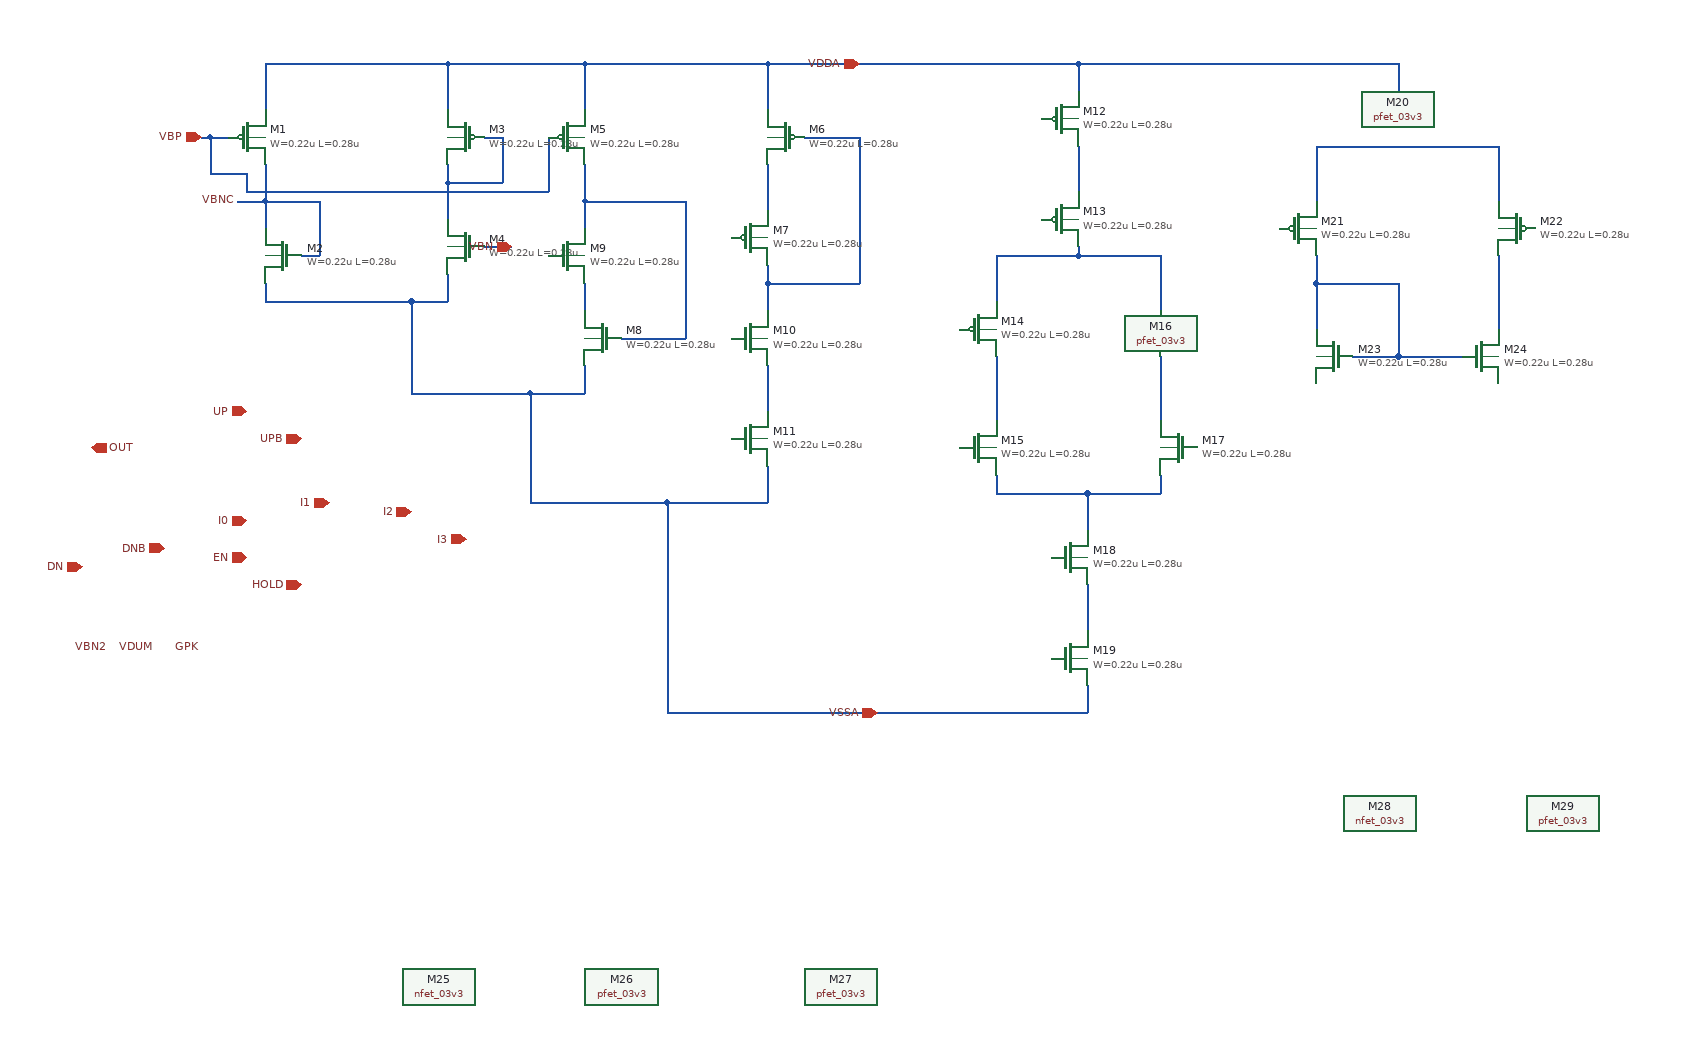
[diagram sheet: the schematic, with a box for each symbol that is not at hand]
v {xschem version=3.4.8RC file_version=1.3}
G {}
K {}
V {}
S {}
F {}
E {}
N -330 -30 -330 -0 {lab=VBNC}
N -130 -50 -130 -10 {lab=#net1}
N -290 30 -270 30 {lab=VBNC}
N -270 -30 -270 30 {lab=VBNC}
N -330 -30 -270 -30 {lab=VBNC}
N -330 -70 -330 -30 {lab=VBNC}
N -90 -100 -70 -100 {lab=#net1}
N -70 -100 -70 -50 {lab=#net1}
N -130 -50 -70 -50 {lab=#net1}
N -130 -70 -130 -50 {lab=#net1}
N -330 -180 -330 -130 {lab=VDDA}
N -330 -180 -130 -180 {lab=VDDA}
N -130 -180 -130 -130 {lab=VDDA}
N 20 -30 130 -30 {lab=#net2}
N 20 -70 20 -30 {lab=#net2}
N 260 -100 320 -100 {lab=#net3}
N 20 -180 20 -130 {lab=VDDA}
N 20 -180 220 -180 {lab=VDDA}
N 220 -180 220 -130 {lab=VDDA}
N -130 -180 20 -180 {lab=VDDA}
N 220 -70 220 -20 {lab=#net4}
N 220 150 220 200 {lab=#net5}
N 220 60 220 90 {lab=#net3}
N 320 -100 320 60 {lab=#net3}
N 220 60 320 60 {lab=#net3}
N 220 40 220 60 {lab=#net3}
N 20 60 20 90 {lab=#net6}
N 20 -30 20 -0 {lab=#net2}
N 60 120 130 120 {lab=#net2}
N 130 -30 130 120 {lab=#net2}
N 570 390 570 440 {lab=#net7}
N 560 -90 560 -40 {lab=#net8}
N 470 30 470 80 {lab=#net9}
N 560 30 650 30 {lab=#net9}
N 650 30 650 90 {lab=#net9}
N 560 20 560 30 {lab=#net9}
N 470 30 560 30 {lab=#net9}
N 470 140 470 210 {lab=#net10}
N 650 140 650 210 {lab=#net11}
N 470 270 470 290 {lab=#net12}
N 570 290 650 290 {lab=#net12}
N 650 270 650 290 {lab=#net12}
N 570 290 570 330 {lab=#net12}
N 470 290 570 290 {lab=#net12}
N 820 -90 820 -30 {lab=#net13}
N 820 -90 1020 -90 {lab=#net13}
N 1020 -90 1020 -30 {lab=#net13}
N 820 60 820 110 {lab=#net14}
N 1020 30 1020 110 {lab=#net15}
N 910 140 980 140 {lab=#net14}
N 820 60 910 60 {lab=#net14}
N 820 30 820 60 {lab=#net14}
N 910 60 910 140 {lab=#net14}
N 860 140 910 140 {lab=#net14}
N 560 -180 910 -180 {lab=VDDA}
N 910 -180 910 -150 {lab=VDDA}
N 560 -180 560 -150 {lab=VDDA}
N 220 -180 560 -180 {lab=VDDA}
N -390 -100 -370 -100 {lab=VBP}
N -360 -30 -330 -30 {lab=VBNC}
N -330 60 -330 80 {lab=VSSA}
N -170 80 -130 80 {lab=VSSA}
N -130 50 -130 80 {lab=VSSA}
N 20 150 20 180 {lab=VSSA}
N -40 180 20 180 {lab=VSSA}
N -170 80 -170 180 {lab=VSSA}
N -330 80 -170 80 {lab=VSSA}
N 220 260 220 300 {lab=VSSA}
N 110 300 220 300 {lab=VSSA}
N -40 180 -40 300 {lab=VSSA}
N -170 180 -40 180 {lab=VSSA}
N 570 500 570 530 {lab=VSSA}
N 110 530 570 530 {lab=VSSA}
N 110 300 110 530 {lab=VSSA}
N -40 300 110 300 {lab=VSSA}
N -20 -100 -20 -40 {lab=VBP}
N -350 -40 -20 -40 {lab=VBP}
N -350 -60 -350 -40 {lab=VBP}
N -390 -60 -350 -60 {lab=VBP}
N -390 -100 -390 -60 {lab=VBP}
N -400 -100 -390 -100 {lab=VBP}
N -90 20 -60 20 {lab=VBN}
C {/foss/pdks/gf180mcuD/libs.tech/xschem/symbols/pfet_03v3.sym} -350 -100 0 0 {name=M1
L=0.28u
W=0.22u
nf=1
m=1
ad="'int((nf+1)/2) * W/nf * 0.18u'"
pd="'2*int((nf+1)/2) * (W/nf + 0.18u)'"
as="'int((nf+2)/2) * W/nf * 0.18u'"
ps="'2*int((nf+2)/2) * (W/nf + 0.18u)'"
nrd="'0.18u / W'" nrs="'0.18u / W'"
sa=0 sb=0 sd=0
model=pfet_03v3
spiceprefix=X
}
C {/foss/pdks/gf180mcuD/libs.tech/xschem/symbols/nfet_03v3.sym} -310 30 2 0 {name=M2
L=0.28u
W=0.22u
nf=1
m=1
ad="'int((nf+1)/2) * W/nf * 0.18u'"
pd="'2*int((nf+1)/2) * (W/nf + 0.18u)'"
as="'int((nf+2)/2) * W/nf * 0.18u'"
ps="'2*int((nf+2)/2) * (W/nf + 0.18u)'"
nrd="'0.18u / W'" nrs="'0.18u / W'"
sa=0 sb=0 sd=0
model=nfet_03v3
spiceprefix=X
}
C {/foss/pdks/gf180mcuD/libs.tech/xschem/symbols/pfet_03v3.sym} -110 -100 0 1 {name=M3
L=0.28u
W=0.22u
nf=1
m=1
ad="'int((nf+1)/2) * W/nf * 0.18u'"
pd="'2*int((nf+1)/2) * (W/nf + 0.18u)'"
as="'int((nf+2)/2) * W/nf * 0.18u'"
ps="'2*int((nf+2)/2) * (W/nf + 0.18u)'"
nrd="'0.18u / W'" nrs="'0.18u / W'"
sa=0 sb=0 sd=0
model=pfet_03v3
spiceprefix=X
}
C {/foss/pdks/gf180mcuD/libs.tech/xschem/symbols/nfet_03v3.sym} -110 20 2 0 {name=M4
L=0.28u
W=0.22u
nf=1
m=1
ad="'int((nf+1)/2) * W/nf * 0.18u'"
pd="'2*int((nf+1)/2) * (W/nf + 0.18u)'"
as="'int((nf+2)/2) * W/nf * 0.18u'"
ps="'2*int((nf+2)/2) * (W/nf + 0.18u)'"
nrd="'0.18u / W'" nrs="'0.18u / W'"
sa=0 sb=0 sd=0
model=nfet_03v3
spiceprefix=X
}
C {/foss/pdks/gf180mcuD/libs.tech/xschem/symbols/pfet_03v3.sym} 0 -100 0 0 {name=M5
L=0.28u
W=0.22u
nf=1
m=1
ad="'int((nf+1)/2) * W/nf * 0.18u'"
pd="'2*int((nf+1)/2) * (W/nf + 0.18u)'"
as="'int((nf+2)/2) * W/nf * 0.18u'"
ps="'2*int((nf+2)/2) * (W/nf + 0.18u)'"
nrd="'0.18u / W'" nrs="'0.18u / W'"
sa=0 sb=0 sd=0
model=pfet_03v3
spiceprefix=X
}
C {/foss/pdks/gf180mcuD/libs.tech/xschem/symbols/pfet_03v3.sym} 240 -100 0 1 {name=M6
L=0.28u
W=0.22u
nf=1
m=1
ad="'int((nf+1)/2) * W/nf * 0.18u'"
pd="'2*int((nf+1)/2) * (W/nf + 0.18u)'"
as="'int((nf+2)/2) * W/nf * 0.18u'"
ps="'2*int((nf+2)/2) * (W/nf + 0.18u)'"
nrd="'0.18u / W'" nrs="'0.18u / W'"
sa=0 sb=0 sd=0
model=pfet_03v3
spiceprefix=X
}
C {/foss/pdks/gf180mcuD/libs.tech/xschem/symbols/pfet_03v3.sym} 200 10 0 0 {name=M7
L=0.28u
W=0.22u
nf=1
m=1
ad="'int((nf+1)/2) * W/nf * 0.18u'"
pd="'2*int((nf+1)/2) * (W/nf + 0.18u)'"
as="'int((nf+2)/2) * W/nf * 0.18u'"
ps="'2*int((nf+2)/2) * (W/nf + 0.18u)'"
nrd="'0.18u / W'" nrs="'0.18u / W'"
sa=0 sb=0 sd=0
model=pfet_03v3
spiceprefix=X
}
C {/foss/pdks/gf180mcuD/libs.tech/xschem/symbols/nfet_03v3.sym} 40 120 2 0 {name=M8
L=0.28u
W=0.22u
nf=1
m=1
ad="'int((nf+1)/2) * W/nf * 0.18u'"
pd="'2*int((nf+1)/2) * (W/nf + 0.18u)'"
as="'int((nf+2)/2) * W/nf * 0.18u'"
ps="'2*int((nf+2)/2) * (W/nf + 0.18u)'"
nrd="'0.18u / W'" nrs="'0.18u / W'"
sa=0 sb=0 sd=0
model=nfet_03v3
spiceprefix=X
}
C {/foss/pdks/gf180mcuD/libs.tech/xschem/symbols/nfet_03v3.sym} 0 30 0 0 {name=M9
L=0.28u
W=0.22u
nf=1
m=1
ad="'int((nf+1)/2) * W/nf * 0.18u'"
pd="'2*int((nf+1)/2) * (W/nf + 0.18u)'"
as="'int((nf+2)/2) * W/nf * 0.18u'"
ps="'2*int((nf+2)/2) * (W/nf + 0.18u)'"
nrd="'0.18u / W'" nrs="'0.18u / W'"
sa=0 sb=0 sd=0
model=nfet_03v3
spiceprefix=X
}
C {/foss/pdks/gf180mcuD/libs.tech/xschem/symbols/nfet_03v3.sym} 200 120 0 0 {name=M10
L=0.28u
W=0.22u
nf=1
m=1
ad="'int((nf+1)/2) * W/nf * 0.18u'"
pd="'2*int((nf+1)/2) * (W/nf + 0.18u)'"
as="'int((nf+2)/2) * W/nf * 0.18u'"
ps="'2*int((nf+2)/2) * (W/nf + 0.18u)'"
nrd="'0.18u / W'" nrs="'0.18u / W'"
sa=0 sb=0 sd=0
model=nfet_03v3
spiceprefix=X
}
C {/foss/pdks/gf180mcuD/libs.tech/xschem/symbols/nfet_03v3.sym} 200 230 0 0 {name=M11
L=0.28u
W=0.22u
nf=1
m=1
ad="'int((nf+1)/2) * W/nf * 0.18u'"
pd="'2*int((nf+1)/2) * (W/nf + 0.18u)'"
as="'int((nf+2)/2) * W/nf * 0.18u'"
ps="'2*int((nf+2)/2) * (W/nf + 0.18u)'"
nrd="'0.18u / W'" nrs="'0.18u / W'"
sa=0 sb=0 sd=0
model=nfet_03v3
spiceprefix=X
}
C {/foss/pdks/gf180mcuD/libs.tech/xschem/symbols/pfet_03v3.sym} 540 -120 0 0 {name=M12
L=0.28u
W=0.22u
nf=1
m=1
ad="'int((nf+1)/2) * W/nf * 0.18u'"
pd="'2*int((nf+1)/2) * (W/nf + 0.18u)'"
as="'int((nf+2)/2) * W/nf * 0.18u'"
ps="'2*int((nf+2)/2) * (W/nf + 0.18u)'"
nrd="'0.18u / W'" nrs="'0.18u / W'"
sa=0 sb=0 sd=0
model=pfet_03v3
spiceprefix=X
}
C {/foss/pdks/gf180mcuD/libs.tech/xschem/symbols/pfet_03v3.sym} 540 -10 0 0 {name=M13
L=0.28u
W=0.22u
nf=1
m=1
ad="'int((nf+1)/2) * W/nf * 0.18u'"
pd="'2*int((nf+1)/2) * (W/nf + 0.18u)'"
as="'int((nf+2)/2) * W/nf * 0.18u'"
ps="'2*int((nf+2)/2) * (W/nf + 0.18u)'"
nrd="'0.18u / W'" nrs="'0.18u / W'"
sa=0 sb=0 sd=0
model=pfet_03v3
spiceprefix=X
}
C {/foss/pdks/gf180mcuD/libs.tech/xschem/symbols/pfet_03v3.sym} 450 110 0 0 {name=M14
L=0.28u
W=0.22u
nf=1
m=1
ad="'int((nf+1)/2) * W/nf * 0.18u'"
pd="'2*int((nf+1)/2) * (W/nf + 0.18u)'"
as="'int((nf+2)/2) * W/nf * 0.18u'"
ps="'2*int((nf+2)/2) * (W/nf + 0.18u)'"
nrd="'0.18u / W'" nrs="'0.18u / W'"
sa=0 sb=0 sd=0
model=pfet_03v3
spiceprefix=X
}
C {/foss/pdks/gf180mcuD/libs.tech/xschem/symbols/nfet_03v3.sym} 450 240 0 0 {name=M15
L=0.28u
W=0.22u
nf=1
m=1
ad="'int((nf+1)/2) * W/nf * 0.18u'"
pd="'2*int((nf+1)/2) * (W/nf + 0.18u)'"
as="'int((nf+2)/2) * W/nf * 0.18u'"
ps="'2*int((nf+2)/2) * (W/nf + 0.18u)'"
nrd="'0.18u / W'" nrs="'0.18u / W'"
sa=0 sb=0 sd=0
model=nfet_03v3
spiceprefix=X
}
C {/foss/pdks/gf180mcuD/libs.tech/xschem/symbols/pfet_03v3.sym} 670 110 0 1 {name=M16
L=0.28u
W=0.22u
nf=1
m=1
ad="'int((nf+1)/2) * W/nf * 0.18u'"
pd="'2*int((nf+1)/2) * (W/nf + 0.18u)'"
as="'int((nf+2)/2) * W/nf * 0.18u'"
ps="'2*int((nf+2)/2) * (W/nf + 0.18u)'"
nrd="'0.18u / W'" nrs="'0.18u / W'"
sa=0 sb=0 sd=0
model=pfet_03v3
spiceprefix=X
}
C {/foss/pdks/gf180mcuD/libs.tech/xschem/symbols/nfet_03v3.sym} 670 240 2 0 {name=M17
L=0.28u
W=0.22u
nf=1
m=1
ad="'int((nf+1)/2) * W/nf * 0.18u'"
pd="'2*int((nf+1)/2) * (W/nf + 0.18u)'"
as="'int((nf+2)/2) * W/nf * 0.18u'"
ps="'2*int((nf+2)/2) * (W/nf + 0.18u)'"
nrd="'0.18u / W'" nrs="'0.18u / W'"
sa=0 sb=0 sd=0
model=nfet_03v3
spiceprefix=X
}
C {/foss/pdks/gf180mcuD/libs.tech/xschem/symbols/nfet_03v3.sym} 550 360 0 0 {name=M18
L=0.28u
W=0.22u
nf=1
m=1
ad="'int((nf+1)/2) * W/nf * 0.18u'"
pd="'2*int((nf+1)/2) * (W/nf + 0.18u)'"
as="'int((nf+2)/2) * W/nf * 0.18u'"
ps="'2*int((nf+2)/2) * (W/nf + 0.18u)'"
nrd="'0.18u / W'" nrs="'0.18u / W'"
sa=0 sb=0 sd=0
model=nfet_03v3
spiceprefix=X
}
C {/foss/pdks/gf180mcuD/libs.tech/xschem/symbols/nfet_03v3.sym} 550 470 0 0 {name=M19
L=0.28u
W=0.22u
nf=1
m=1
ad="'int((nf+1)/2) * W/nf * 0.18u'"
pd="'2*int((nf+1)/2) * (W/nf + 0.18u)'"
as="'int((nf+2)/2) * W/nf * 0.18u'"
ps="'2*int((nf+2)/2) * (W/nf + 0.18u)'"
nrd="'0.18u / W'" nrs="'0.18u / W'"
sa=0 sb=0 sd=0
model=nfet_03v3
spiceprefix=X
}
C {/foss/pdks/gf180mcuD/libs.tech/xschem/symbols/pfet_03v3.sym} 890 -120 0 0 {name=M20
L=0.28u
W=0.22u
nf=1
m=1
ad="'int((nf+1)/2) * W/nf * 0.18u'"
pd="'2*int((nf+1)/2) * (W/nf + 0.18u)'"
as="'int((nf+2)/2) * W/nf * 0.18u'"
ps="'2*int((nf+2)/2) * (W/nf + 0.18u)'"
nrd="'0.18u / W'" nrs="'0.18u / W'"
sa=0 sb=0 sd=0
model=pfet_03v3
spiceprefix=X
}
C {/foss/pdks/gf180mcuD/libs.tech/xschem/symbols/pfet_03v3.sym} 800 0 0 0 {name=M21
L=0.28u
W=0.22u
nf=1
m=1
ad="'int((nf+1)/2) * W/nf * 0.18u'"
pd="'2*int((nf+1)/2) * (W/nf + 0.18u)'"
as="'int((nf+2)/2) * W/nf * 0.18u'"
ps="'2*int((nf+2)/2) * (W/nf + 0.18u)'"
nrd="'0.18u / W'" nrs="'0.18u / W'"
sa=0 sb=0 sd=0
model=pfet_03v3
spiceprefix=X
}
C {/foss/pdks/gf180mcuD/libs.tech/xschem/symbols/pfet_03v3.sym} 1040 0 0 1 {name=M22
L=0.28u
W=0.22u
nf=1
m=1
ad="'int((nf+1)/2) * W/nf * 0.18u'"
pd="'2*int((nf+1)/2) * (W/nf + 0.18u)'"
as="'int((nf+2)/2) * W/nf * 0.18u'"
ps="'2*int((nf+2)/2) * (W/nf + 0.18u)'"
nrd="'0.18u / W'" nrs="'0.18u / W'"
sa=0 sb=0 sd=0
model=pfet_03v3
spiceprefix=X
}
C {/foss/pdks/gf180mcuD/libs.tech/xschem/symbols/nfet_03v3.sym} 840 140 2 0 {name=M23
L=0.28u
W=0.22u
nf=1
m=1
ad="'int((nf+1)/2) * W/nf * 0.18u'"
pd="'2*int((nf+1)/2) * (W/nf + 0.18u)'"
as="'int((nf+2)/2) * W/nf * 0.18u'"
ps="'2*int((nf+2)/2) * (W/nf + 0.18u)'"
nrd="'0.18u / W'" nrs="'0.18u / W'"
sa=0 sb=0 sd=0
model=nfet_03v3
spiceprefix=X
}
C {/foss/pdks/gf180mcuD/libs.tech/xschem/symbols/nfet_03v3.sym} 1000 140 0 0 {name=M24
L=0.28u
W=0.22u
nf=1
m=1
ad="'int((nf+1)/2) * W/nf * 0.18u'"
pd="'2*int((nf+1)/2) * (W/nf + 0.18u)'"
as="'int((nf+2)/2) * W/nf * 0.18u'"
ps="'2*int((nf+2)/2) * (W/nf + 0.18u)'"
nrd="'0.18u / W'" nrs="'0.18u / W'"
sa=0 sb=0 sd=0
model=nfet_03v3
spiceprefix=X
}
C {/foss/pdks/gf180mcuD/libs.tech/xschem/symbols/nfet_03v3.sym} -140 830 2 1 {name=M25
L=0.28u
W=0.22u
nf=1
m=1
ad="'int((nf+1)/2) * W/nf * 0.18u'"
pd="'2*int((nf+1)/2) * (W/nf + 0.18u)'"
as="'int((nf+2)/2) * W/nf * 0.18u'"
ps="'2*int((nf+2)/2) * (W/nf + 0.18u)'"
nrd="'0.18u / W'" nrs="'0.18u / W'"
sa=0 sb=0 sd=0
model=nfet_03v3
spiceprefix=X
}
C {/foss/pdks/gf180mcuD/libs.tech/xschem/symbols/pfet_03v3.sym} 60 830 0 0 {name=M26
L=0.28u
W=0.22u
nf=1
m=1
ad="'int((nf+1)/2) * W/nf * 0.18u'"
pd="'2*int((nf+1)/2) * (W/nf + 0.18u)'"
as="'int((nf+2)/2) * W/nf * 0.18u'"
ps="'2*int((nf+2)/2) * (W/nf + 0.18u)'"
nrd="'0.18u / W'" nrs="'0.18u / W'"
sa=0 sb=0 sd=0
model=pfet_03v3
spiceprefix=X
}
C {/foss/pdks/gf180mcuD/libs.tech/xschem/symbols/pfet_03v3.sym} 300 830 0 0 {name=M27
L=0.28u
W=0.22u
nf=1
m=1
ad="'int((nf+1)/2) * W/nf * 0.18u'"
pd="'2*int((nf+1)/2) * (W/nf + 0.18u)'"
as="'int((nf+2)/2) * W/nf * 0.18u'"
ps="'2*int((nf+2)/2) * (W/nf + 0.18u)'"
nrd="'0.18u / W'" nrs="'0.18u / W'"
sa=0 sb=0 sd=0
model=pfet_03v3
spiceprefix=X
}
C {/foss/pdks/gf180mcuD/libs.tech/xschem/symbols/nfet_03v3.sym} 890 640 2 1 {name=M28
L=0.28u
W=0.22u
nf=1
m=1
ad="'int((nf+1)/2) * W/nf * 0.18u'"
pd="'2*int((nf+1)/2) * (W/nf + 0.18u)'"
as="'int((nf+2)/2) * W/nf * 0.18u'"
ps="'2*int((nf+2)/2) * (W/nf + 0.18u)'"
nrd="'0.18u / W'" nrs="'0.18u / W'"
sa=0 sb=0 sd=0
model=nfet_03v3
spiceprefix=X
}
C {/foss/pdks/gf180mcuD/libs.tech/xschem/symbols/pfet_03v3.sym} 1090 640 0 0 {name=M29
L=0.28u
W=0.22u
nf=1
m=1
ad="'int((nf+1)/2) * W/nf * 0.18u'"
pd="'2*int((nf+1)/2) * (W/nf + 0.18u)'"
as="'int((nf+2)/2) * W/nf * 0.18u'"
ps="'2*int((nf+2)/2) * (W/nf + 0.18u)'"
nrd="'0.18u / W'" nrs="'0.18u / W'"
sa=0 sb=0 sd=0
model=pfet_03v3
spiceprefix=X
}
C {iopin.sym} 320 -180 3 0 {name=p1 lab=VDDA
}
C {ipin.sym} -400 -100 0 0 {name=p2 lab=VBP}
C {opin.sym} -520 240 0 0 {name=p3 lab=OUT}
C {lab_wire.sym} -360 -30 0 0 {name=p4 sig_type=std_logic lab=VBNC}
C {iopin.sym} 340 530 1 0 {name=p5 lab=VSSA}
C {ipin.sym} -60 20 1 0 {name=p6 lab=VBN}
C {ipin.sym} -350 200 0 0 {name=p7 lab=UP}
C {ipin.sym} -290 230 0 0 {name=p8 lab=UPB}
C {ipin.sym} -530 370 0 0 {name=p9 lab=DN}
C {ipin.sym} -440 350 0 0 {name=p10 lab=DNB}
C {ipin.sym} -350 360 0 0 {name=p11 lab=EN}
C {ipin.sym} -290 390 0 0 {name=p12 lab=HOLD}
C {ipin.sym} -350 320 0 0 {name=p13 lab=I0}
C {ipin.sym} -260 300 0 0 {name=p14 lab=I1}
C {ipin.sym} -170 310 0 0 {name=p15 lab=I2}
C {ipin.sym} -110 340 0 0 {name=p16 lab=I3}
C {lab_wire.sym} -500 460 0 0 {name=p17 sig_type=std_logic lab=VBN2}
C {lab_wire.sym} -450 460 0 0 {name=p18 sig_type=std_logic lab=VDUM}
C {lab_wire.sym} -400 460 0 0 {name=p19 sig_type=std_logic lab=GPK}
